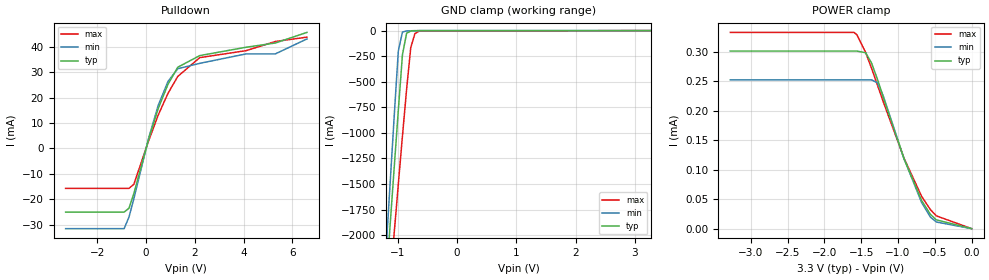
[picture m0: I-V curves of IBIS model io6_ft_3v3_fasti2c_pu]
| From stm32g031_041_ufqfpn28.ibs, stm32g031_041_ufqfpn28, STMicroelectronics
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[Model]  io6_ft_3v3_fasti2c_pu
Model_type I/O_open_drain
Polarity   Non-Inverting
Enable   Active-Low
Vinl =   0.990000V
Vinh =   2.310000V
Vmeas =  1.650000V
Cref =   50.000000pF
Rref =   100.000000M
Vref =   0.0V
C_comp   1.290400pF   1.272500pF   1.305600pF
[Temperature Range]   25.000000   -40.000000   0.125000k
[Pullup Reference]   3.300000V   3.000000V   3.600000V
[Pulldown Reference]   0.0V   0.0V   0.0V
[POWER Clamp Reference]   3.300000V   3.000000V   3.600000V
[GND Clamp Reference]   0.0V   0.0V   0.0V
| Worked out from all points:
|   slope of the pulldown table from 0 to 0.495 V, typ, clamps not added: 31.8 ohm
|   GND clamp passes 1 mA (typ) near -0.65 V on its own axis
[Pulldown]
|Voltage   I(typ)   I(min)   I(max)
-3.3V     -25.03mA   -31.54mA   -15.7mA
-900mV    -25.03mA   -31.54mA   -15.7mA
-700mV    -23.48mA   -26.95mA   -15.7mA
-500mV    -17.69mA   -19.75mA   -14.07mA
100mV     3.479mA    3.853mA    2.862mA
500mV     15.71mA    16.96mA    13.17mA
900mV     25.22mA    26.33mA    21.66mA
1.3V      31.91mA    31.32mA    28.29mA
2.2V      36.48mA    33.43mA    35.69mA
4.1V      39.76mA    37.15mA    38.42mA
5.3V      41.43mA    37.15mA    42.02mA
6.6V      45.6mA     43.04mA    43.74mA
[GND_clamp]
|Voltage   I(typ)   I(min)   I(max)
-3.3V     -9.61A     -9.635A    -9.699A
-1.2V     -2.493A    -2.184A    -2.958A
-1.13V    -1.917A    -1.512A    -2.469A
-1.06V    -1.345A    -845.6mA   -1.983A
-990mV    -779.8mA   -200.2mA   -1.503A
-920mV    -235.5mA   -14.18mA   -1.03A
-850mV    -26.06mA   -3.338mA   -574.2mA
-780mV    -4.499mA   -1.808mA   -166.4mA
-710mV    -1.722mA   -869.6uA   -29.45mA
-640mV    -806.7uA   -283.7uA   -6.281mA
3.28V     0A         0A         0A
[POWER_clamp]
|Voltage   I(typ)   I(min)   I(max)
-3.28V    300.8uA    252uA      332.4uA
-1.6V     300.8uA    252uA      332.4uA
-1.56V    300.8uA    252uA      328.4uA
-1.44V    297.9uA    252uA      298.3uA
-1.36V    280.4uA    252uA      271.4uA
-1.28V    252.9uA    246.9uA    243.1uA
-1.2V     222.5uA    224.3uA    214.5uA
-920mV    118.6uA    118.8uA    119.5uA
-680mV    47.6uA     44.33uA    54.63uA
-560mV    24.08uA    19.48uA    32.08uA
-480mV    14.89uA    11.29uA    21.67uA
0V        0A         0A         0A
[Ramp]
| variable   typ   min   max
dV/dt_r  1.07348/2.09581n   0.96120/2.04204n   1.029/2.37702n
dV/dt_f  1.02792/1.87135n   0.94800/1.89025n   1.02144/1.93042n
R_load = 50.000000
